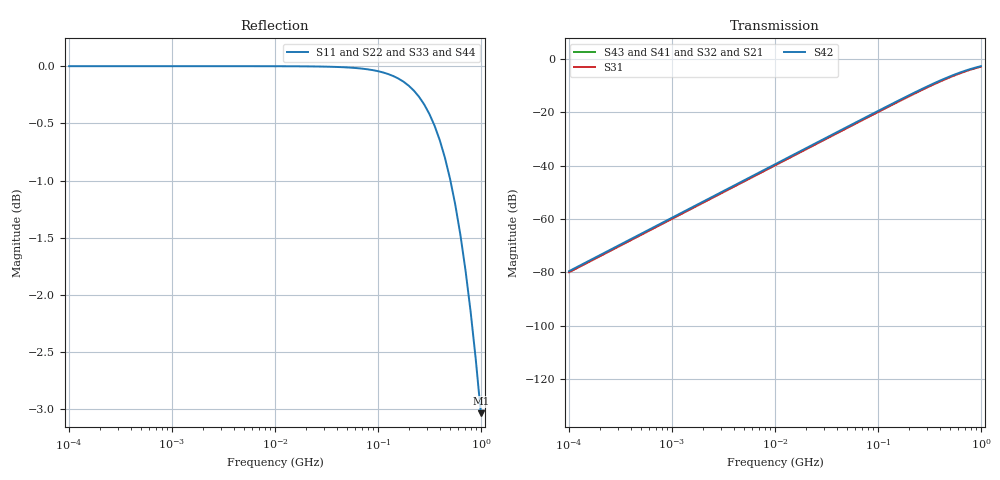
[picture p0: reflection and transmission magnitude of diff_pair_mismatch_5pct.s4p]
# Hz S RI R 50
! golden: diff_pair_mismatch_5pct
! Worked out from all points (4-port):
!   81 points, 100 kHz to 1 GHz, reference 50 ohm
!   strongest paths, dB at 100 kHz, 1 MHz, 10 MHz, 100 MHz, 1 GHz:
!     S42: -79.5, -59.5, -39.5, -19.6, -2.8
!     S31: -80.0, -60.0, -40.0, -20.0, -3.0
!     S43: -, -, -, -, -
!     S41: -, -, -, -, -
!     S32: -, -, -, -, -
!     S21: -, -, -, -, -
!   lowest |S11| = -3.0 dB at 1 GHz (marker M1), VSWR 5.78, Z = 10.1 + j20.1 ohm
!   |S11| at or under -10 dB: nowhere
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100000  -1 0.000101  0 0  -1.01e-08 -0.000101  0 0
        0 0  -1 0.000106  0 0  -1.11e-08 -0.000106
        -1.01e-08 -0.000101  0 0  -1 0.000101  0 0
        0 0  -1.11e-08 -0.000106  0 0  -1 0.000106
1.995262e7  -0.9996 0.0201  0 0  -0.000402 -0.0201  0 0
            0 0  -0.9996 0.0211  0 0  -0.000443 -0.0211
            -0.000402 -0.0201  0 0  -0.9996 0.0201  0 0
            0 0  -0.000443 -0.0211  0 0  -0.9996 0.0211
6.309573e7  -0.996 0.0632  0 0  -0.00401 -0.0632  0 0
            0 0  -0.9956 0.0663  0 0  -0.00442 -0.0663
            -0.00401 -0.0632  0 0  -0.996 0.0632  0 0
            0 0  -0.00442 -0.0663  0 0  -0.9956 0.0663
1.584893e8  -0.9752 0.1554  0 0  -0.0248 -0.1554  0 0
            0 0  -0.9728 0.1627  0 0  -0.0272 -0.1627
            -0.0248 -0.1554  0 0  -0.9752 0.1554  0 0
            0 0  -0.0272 -0.1627  0 0  -0.9728 0.1627
3.981072e8  -0.8619 0.345  0 0  -0.1381 -0.345  0 0
            0 0  -0.8499 0.3572  0 0  -0.1501 -0.3572
            -0.1381 -0.345  0 0  -0.8619 0.345  0 0
            0 0  -0.1501 -0.3572  0 0  -0.8499 0.3572
7.079458e8  -0.6638 0.4724  0 0  -0.3362 -0.4724  0 0
            0 0  -0.6417 0.4795  0 0  -0.3583 -0.4795
            -0.3362 -0.4724  0 0  -0.6638 0.4724  0 0
            0 0  -0.3583 -0.4795  0 0  -0.6417 0.4795
1e9  -0.4974 0.5  0 0  -0.5026 -0.5  0 0
     0 0  -0.473 0.4993  0 0  -0.527 -0.4993
     -0.5026 -0.5  0 0  -0.4974 0.5  0 0
     0 0  -0.527 -0.4993  0 0  -0.473 0.4993
